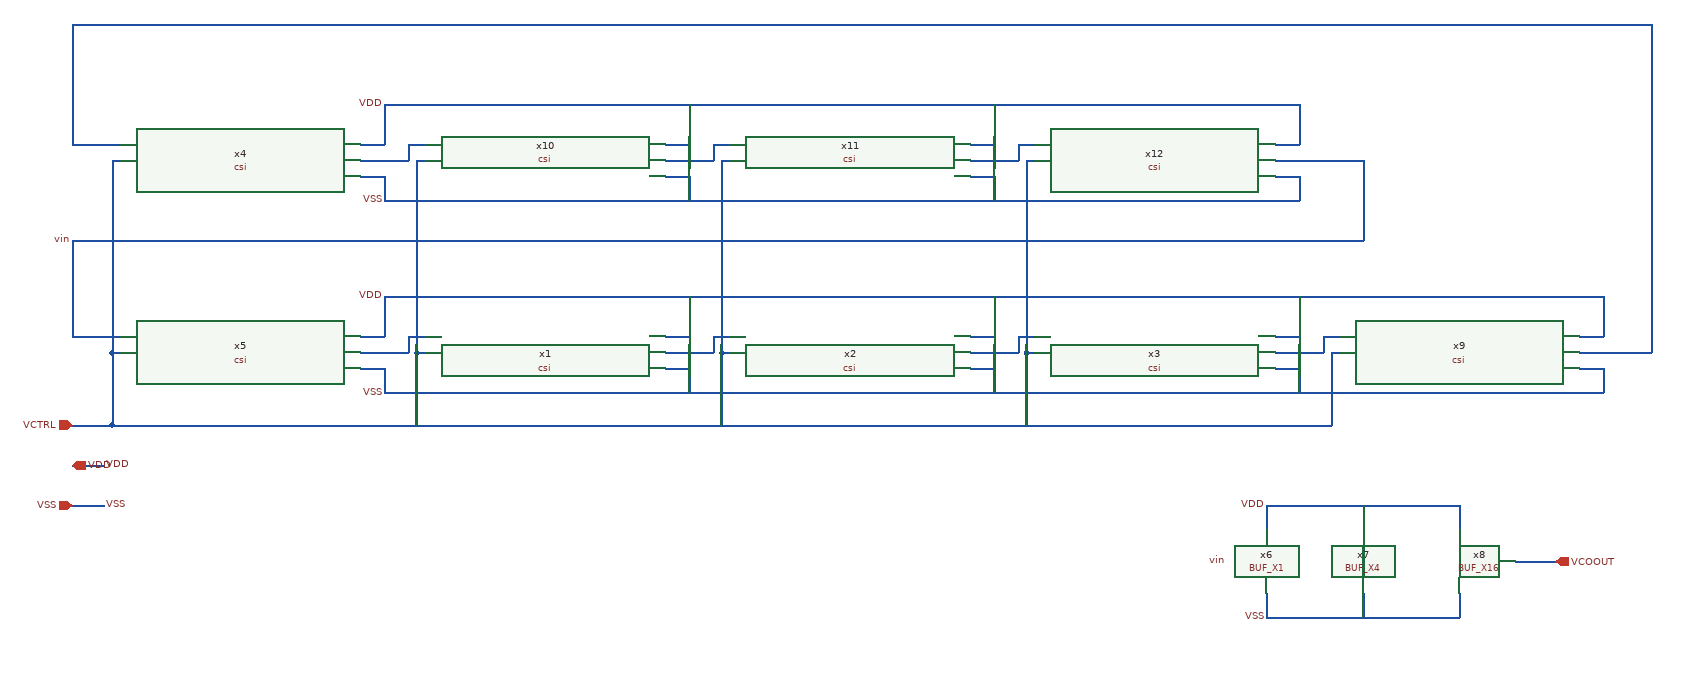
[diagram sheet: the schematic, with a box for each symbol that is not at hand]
v {xschem version=3.4.8RC file_version=1.2}
G {}
K {}
V {}
S {}
E {}
N -1560 -510 -1560 -490 {
lab=VDD}
N -1590 -460 -1560 -460 {lab=VDD}
N -1560 -490 -1560 -460 {lab=VDD}
N -1950 -460 -1890 -460 {lab=vin}
N -1530 -460 -1510 -460 {lab=#net1}
N -1530 -460 -1530 -440 {lab=#net1}
N -1590 -440 -1530 -440 {lab=#net1}
N -1180 -510 -1180 -490 {
lab=VDD}
N -1210 -460 -1180 -460 {lab=VDD}
N -1180 -490 -1180 -460 {lab=VDD}
N -1180 -420 -1180 -390 {lab=VSS}
N -1210 -420 -1180 -420 {lab=VSS}
N -1150 -460 -1130 -460 {lab=#net2}
N -1150 -460 -1150 -440 {lab=#net2}
N -1210 -440 -1150 -440 {lab=#net2}
N -800 -510 -800 -490 {
lab=VDD}
N -830 -460 -800 -460 {lab=VDD}
N -800 -490 -800 -460 {lab=VDD}
N -800 -420 -800 -390 {lab=VSS}
N -830 -420 -800 -420 {lab=VSS}
N -770 -460 -750 -460 {lab=#net3}
N -770 -460 -770 -440 {lab=#net3}
N -830 -440 -770 -440 {lab=#net3}
N -420 -510 -420 -490 {
lab=VDD}
N -450 -460 -420 -460 {lab=VDD}
N -420 -490 -420 -460 {lab=VDD}
N -420 -420 -420 -390 {lab=VSS}
N -450 -420 -420 -420 {lab=VSS}
N -390 -460 -370 -460 {lab=#net4}
N -390 -460 -390 -440 {lab=#net4}
N -450 -440 -390 -440 {lab=#net4}
N -1950 -850 20 -850 {lab=#net5}
N -1560 -420 -1560 -400 {lab=VSS}
N -1560 -400 -1560 -390 {lab=VSS}
N -1590 -420 -1560 -420 {lab=VSS}
N -1560 -750 -1560 -730 {
lab=VDD}
N -1590 -700 -1560 -700 {lab=VDD}
N -1560 -730 -1560 -700 {lab=VDD}
N -1530 -700 -1510 -700 {lab=#net6}
N -1530 -700 -1530 -680 {lab=#net6}
N -1590 -680 -1530 -680 {lab=#net6}
N -1180 -750 -1180 -730 {
lab=VDD}
N -1210 -700 -1180 -700 {lab=VDD}
N -1180 -730 -1180 -700 {lab=VDD}
N -1180 -660 -1180 -630 {lab=VSS}
N -1210 -660 -1180 -660 {lab=VSS}
N -1150 -700 -1130 -700 {lab=#net7}
N -1150 -700 -1150 -680 {lab=#net7}
N -1210 -680 -1150 -680 {lab=#net7}
N -800 -750 -800 -730 {
lab=VDD}
N -830 -700 -800 -700 {lab=VDD}
N -800 -730 -800 -700 {lab=VDD}
N -800 -660 -800 -630 {lab=VSS}
N -830 -660 -800 -660 {lab=VSS}
N -770 -700 -750 -700 {lab=#net8}
N -770 -700 -770 -680 {lab=#net8}
N -830 -680 -770 -680 {lab=#net8}
N -420 -750 -420 -730 {
lab=VDD}
N -450 -700 -420 -700 {lab=VDD}
N -420 -730 -420 -700 {lab=VDD}
N -420 -660 -420 -630 {lab=VSS}
N -450 -660 -420 -660 {lab=VSS}
N -450 -680 -390 -680 {lab=vin}
N -1560 -660 -1560 -640 {lab=VSS}
N -1560 -640 -1560 -630 {lab=VSS}
N -1590 -660 -1560 -660 {lab=VSS}
N 20 -850 20 -590 {lab=#net5}
N -1950 -850 -1950 -700 {lab=#net5}
N -1950 -700 -1890 -700 {lab=#net5}
N -390 -680 -340 -680 {lab=vin}
N -340 -680 -340 -580 {lab=vin}
N -1370 -580 -340 -580 {lab=vin}
N -1950 -580 -1370 -580 {lab=vin}
N -1950 -580 -1950 -470 {lab=vin}
N -1950 -470 -1950 -460 {lab=vin}
N -40 -510 -40 -490 {
lab=VDD}
N -70 -460 -40 -460 {lab=VDD}
N -40 -490 -40 -460 {lab=VDD}
N -40 -420 -40 -390 {lab=VSS}
N -70 -420 -40 -420 {lab=VSS}
N -70 -440 -10 -440 {lab=#net5}
N -10 -440 20 -440 {lab=#net5}
N 20 -590 20 -440 {lab=#net5}
N -220 -250 -220 -220 {lab=VDD}
N -460 -250 -220 -250 {lab=VDD}
N -460 -250 -460 -220 {lab=VDD}
N -340 -250 -340 -220 {lab=VDD}
N -460 -140 -460 -110 {lab=VSS}
N -460 -110 -220 -110 {lab=VSS}
N -220 -140 -220 -110 {lab=VSS}
N -340 -140 -340 -110 {lab=VSS}
N -150 -180 -100 -180 {lab=VCOOUT}
N -1560 -390 -40 -390 {lab=VSS}
N -1560 -510 -40 -510 {lab=VDD}
N -1560 -750 -420 -750 {lab=VDD}
N -1560 -630 -420 -630 {lab=VSS}
N -1520 -680 -1510 -680 {lab=VCTRL}
N -1520 -680 -1520 -440 {lab=VCTRL}
N -1520 -440 -1510 -440 {lab=VCTRL}
N -1520 -440 -1520 -350 {lab=VCTRL}
N -1900 -680 -1890 -680 {lab=VCTRL}
N -1900 -680 -1900 -440 {lab=VCTRL}
N -1900 -440 -1890 -440 {lab=VCTRL}
N -1900 -440 -1900 -350 {lab=VCTRL}
N -1140 -680 -1130 -680 {lab=VCTRL}
N -1140 -680 -1140 -440 {lab=VCTRL}
N -1140 -440 -1130 -440 {lab=VCTRL}
N -1140 -440 -1140 -350 {lab=VCTRL}
N -760 -680 -750 -680 {lab=VCTRL}
N -760 -680 -760 -440 {lab=VCTRL}
N -760 -440 -750 -440 {lab=VCTRL}
N -760 -440 -760 -350 {lab=VCTRL}
N -1900 -350 -380 -350 {lab=VCTRL}
N -380 -440 -380 -350 {lab=VCTRL}
N -380 -440 -370 -440 {lab=VCTRL}
N -1950 -350 -1900 -350 {lab=VCTRL}
N -1950 -300 -1910 -300 {lab=VDD}
N -1950 -250 -1910 -250 {lab=VSS}
C {TR-1um_5_stdcell/BUF_X1.sym} -490 -180 0 0 {name=x6}
C {TR-1um_5_stdcell/BUF_X4.sym} -370 -180 0 0 {name=x7}
C {TR-1um_5_stdcell/BUF_X16.sym} -250 -180 0 0 {name=x8}
C {devices/lab_pin.sym} -510 -180 0 0 {name=p2 sig_type=std_logic lab=vin}
C {csi.sym} -1740 -440 0 0 {name=x5}
C {csi.sym} -1360 -440 0 0 {name=x1}
C {csi.sym} -980 -440 0 0 {name=x2}
C {csi.sym} -600 -440 0 0 {name=x3}
C {csi.sym} -1740 -680 0 0 {name=x4}
C {csi.sym} -1360 -680 0 0 {name=x10}
C {csi.sym} -980 -680 0 0 {name=x11}
C {csi.sym} -600 -680 0 0 {name=x12}
C {devices/lab_pin.sym} -1950 -580 1 0 {name=p1 sig_type=std_logic lab=vin}
C {csi.sym} -220 -440 0 0 {name=x9}
C {devices/opin.sym} -100 -180 0 0 {name=p16 lab=VCOOUT}
C {devices/ipin.sym} -1950 -350 0 0 {name=p10 lab=VCTRL}
C {devices/iopin.sym} -1950 -300 0 1 {name=p4 lab=VDD}
C {devices/iopin.sym} -1950 -250 2 0 {name=p7 lab=VSS}
C {devices/lab_pin.sym} -1910 -300 2 0 {name=p8 sig_type=std_logic lab=VDD}
C {devices/lab_pin.sym} -1910 -250 2 0 {name=p77 sig_type=std_logic lab=VSS}
C {devices/lab_pin.sym} -1560 -750 0 0 {name=p5 sig_type=std_logic lab=VDD}
C {devices/lab_pin.sym} -1560 -510 0 0 {name=p6 sig_type=std_logic lab=VDD}
C {devices/lab_pin.sym} -1560 -630 0 0 {name=p9 sig_type=std_logic lab=VSS}
C {devices/lab_pin.sym} -1560 -390 0 0 {name=p11 sig_type=std_logic lab=VSS}
C {devices/lab_pin.sym} -460 -250 0 0 {name=p3 sig_type=std_logic lab=VDD}
C {devices/lab_pin.sym} -460 -110 0 0 {name=p12 sig_type=std_logic lab=VSS}
